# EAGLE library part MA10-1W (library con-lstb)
PIN HEADER

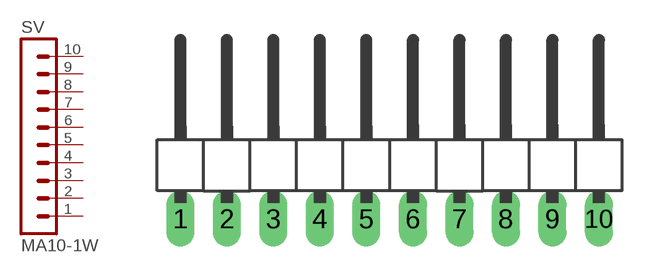
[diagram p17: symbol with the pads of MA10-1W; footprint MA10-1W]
Designator prefix SV

## MA10-1W (OC_FARNELL: unknown; OC_NEWARK: unknown)  [MA10-1W]
1  1  pas
2  2  pas
3  3  pas
4  4  pas
5  5  pas
6  6  pas
7  7  pas
8  8  pas
9  9  pas
10  10  pas

## Footprint MA10-1W (pad centres in mm)
PIN HEADER
drill 1.016 long: 1 -11.43,0; 2 -8.89,0; 3 -6.35,0; 4 -3.81,0; 5 -1.27,0; 6 1.27,0; 7 3.81,0; 8 6.35,0; 9 8.89,0; 10 11.43,0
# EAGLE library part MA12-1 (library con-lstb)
PIN HEADER

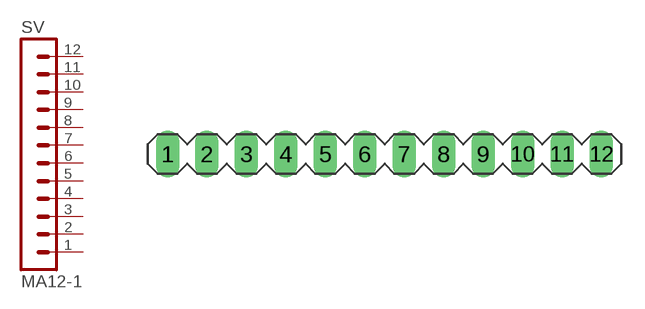
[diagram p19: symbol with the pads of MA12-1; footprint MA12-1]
Designator prefix SV

## MA12-1 (OC_FARNELL: unknown; OC_NEWARK: unknown)  [MA12-1]
1  1  pas
2  2  pas
3  3  pas
4  4  pas
5  5  pas
6  6  pas
7  7  pas
8  8  pas
9  9  pas
10  10  pas
11  11  pas
12  12  pas

## Footprint MA12-1 (pad centres in mm)
PIN HEADER
drill 1.016 long: 1 -13.97,0; 2 -11.43,0; 3 -8.89,0; 4 -6.35,0; 5 -3.81,0; 6 -1.27,0; 7 1.27,0; 8 3.81,0; 9 6.35,0; 10 8.89,0; 11 11.43,0; 12 13.97,0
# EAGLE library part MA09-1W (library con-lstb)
PIN HEADER

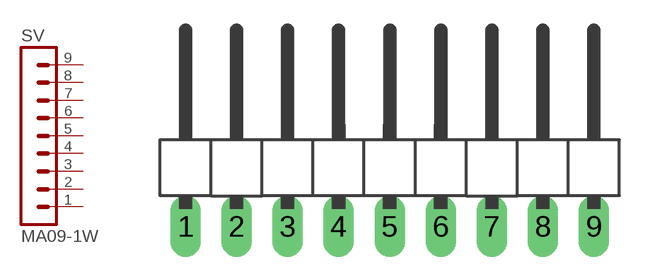
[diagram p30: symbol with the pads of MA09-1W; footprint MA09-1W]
Designator prefix SV

## MA09-1W (OC_FARNELL: unknown; OC_NEWARK: unknown)  [MA09-1W]
1  1  pas
2  2  pas
3  3  pas
4  4  pas
5  5  pas
6  6  pas
7  7  pas
8  8  pas
9  9  pas

## Footprint MA09-1W (pad centres in mm)
PIN HEADER
drill 1.016 long: 1 -10.16,0; 2 -7.62,0; 3 -5.08,0; 4 -2.54,0; 5 0,0; 6 2.54,0; 7 5.08,0; 8 7.62,0; 9 10.16,0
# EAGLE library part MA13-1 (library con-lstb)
PIN HEADER

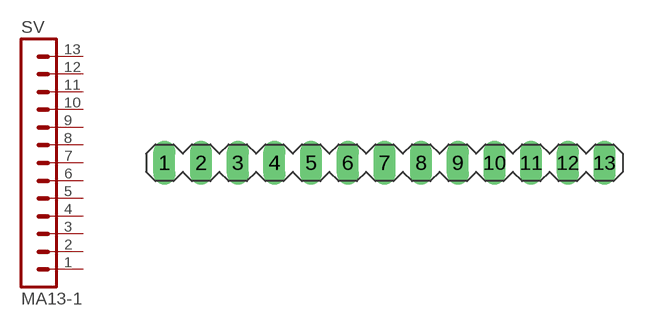
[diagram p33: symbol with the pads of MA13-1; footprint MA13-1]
Designator prefix SV

## MA13-1 (OC_FARNELL: unknown; OC_NEWARK: unknown)  [MA13-1]
1  1  pas
2  2  pas
3  3  pas
4  4  pas
5  5  pas
6  6  pas
7  7  pas
8  8  pas
9  9  pas
10  10  pas
11  11  pas
12  12  pas
13  13  pas

## Footprint MA13-1 (pad centres in mm)
PIN HEADER
drill 1.016 long: 1 -15.24,0; 2 -12.7,0; 3 -10.16,0; 4 -7.62,0; 5 -5.08,0; 6 -2.54,0; 7 0,0; 8 2.54,0; 9 5.08,0; 10 7.62,0; 11 10.16,0; 12 12.7,0; 13 15.24,0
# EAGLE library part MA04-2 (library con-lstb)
PIN HEADER

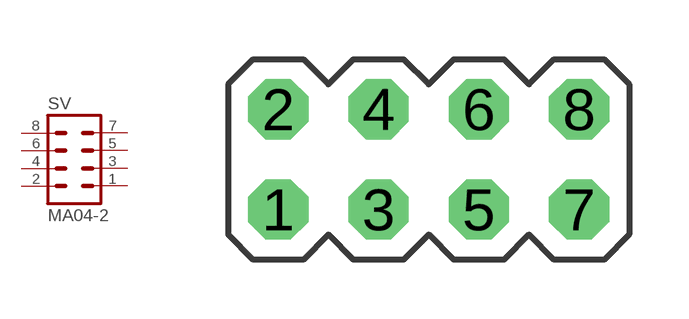
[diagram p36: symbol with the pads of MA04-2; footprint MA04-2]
Designator prefix SV

## MA04-2 (OC_FARNELL: unknown; OC_NEWARK: unknown)  [MA04-2]
1  1  pas
2  2  pas
3  3  pas
4  4  pas
5  5  pas
6  6  pas
7  7  pas
8  8  pas

## Footprint MA04-2 (pad centres in mm)
PIN HEADER
drill 1.016 octagon: 1 -3.81,-1.27; 2 -3.81,1.27; 3 -1.27,-1.27; 4 -1.27,1.27; 5 1.27,-1.27; 6 1.27,1.27; 7 3.81,-1.27; 8 3.81,1.27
